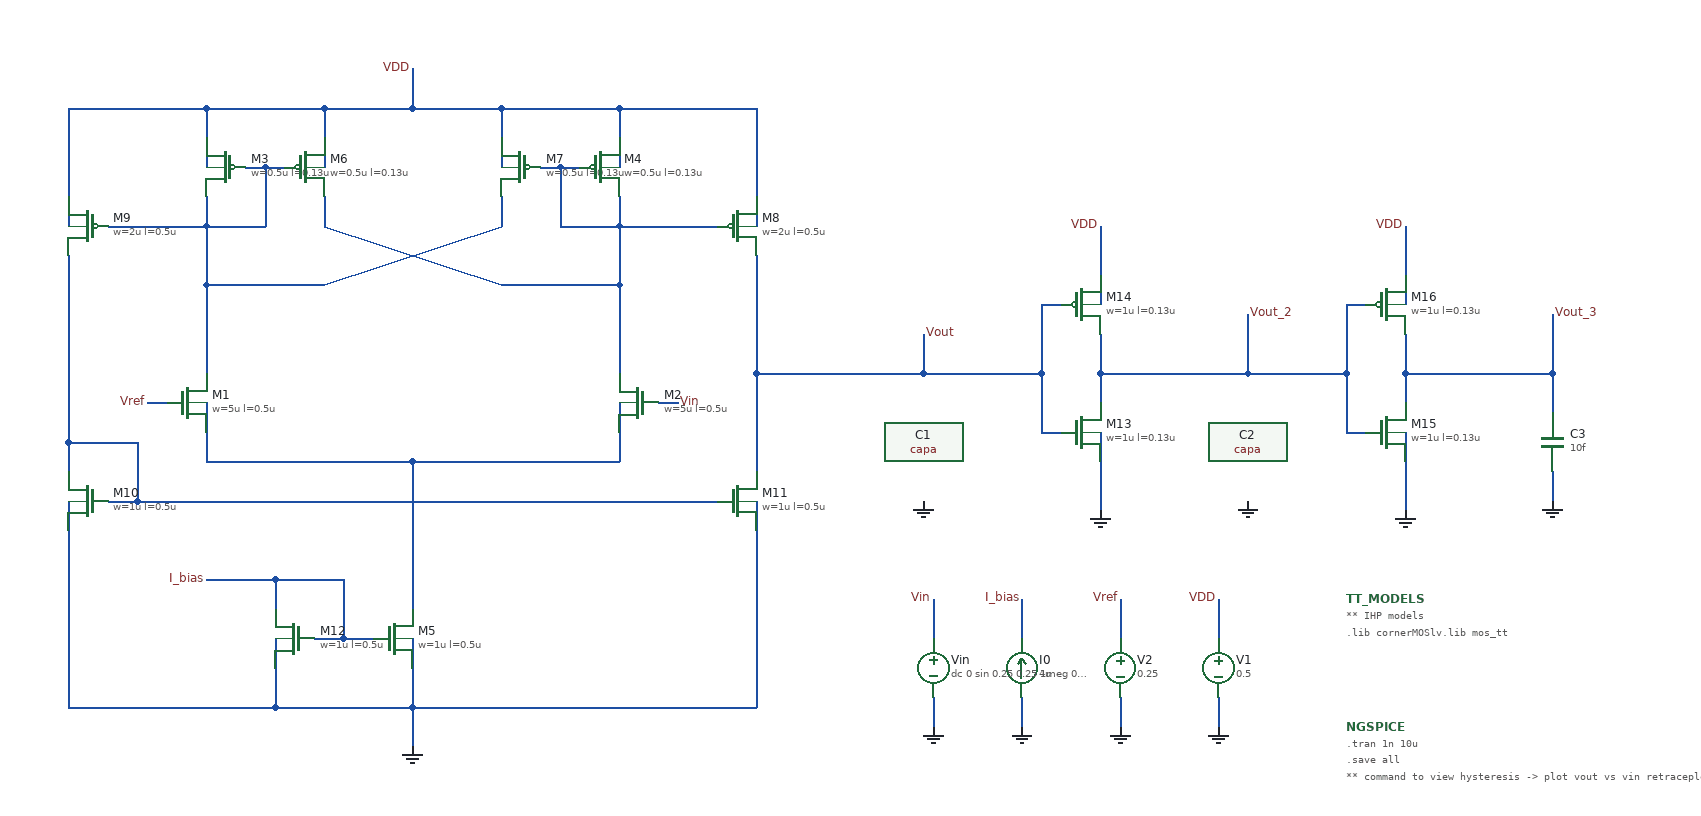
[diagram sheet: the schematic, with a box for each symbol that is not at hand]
v {xschem version=3.4.7 file_version=1.2}
G {}
K {}
V {}
S {}
E {}
P 4 1 1960 -820 {}
N 1310 -1370 1330 -1370 {lab=#net1}
N 1610 -1370 1630 -1370 {lab=#net2}
N 1370 -1250 1550 -1310 {lab=#net1}
N 1250 -1250 1370 -1250 {lab=#net1}
N 1370 -1310 1550 -1250 {lab=#net2}
N 1550 -1250 1670 -1250 {lab=#net2}
N 1250 -1250 1250 -1160 {lab=#net1}
N 1250 -1310 1250 -1250 {lab=#net1}
N 1370 -1340 1370 -1310 {lab=#net2}
N 1550 -1340 1550 -1310 {lab=#net1}
N 1670 -1250 1670 -1160 {lab=#net2}
N 1670 -1310 1670 -1250 {lab=#net2}
N 1310 -1370 1310 -1310 {lab=#net1}
N 1290 -1370 1310 -1370 {lab=#net1}
N 1250 -1310 1310 -1310 {lab=#net1}
N 1250 -1340 1250 -1310 {lab=#net1}
N 1610 -1370 1610 -1310 {lab=#net2}
N 1590 -1370 1610 -1370 {lab=#net2}
N 1610 -1310 1670 -1310 {lab=#net2}
N 1670 -1340 1670 -1310 {lab=#net2}
N 1250 -1430 1250 -1370 {lab=VDD}
N 1550 -1430 1670 -1430 {lab=VDD}
N 1670 -1430 1670 -1370 {lab=VDD}
N 1550 -1430 1550 -1370 {lab=VDD}
N 1460 -1430 1550 -1430 {lab=VDD}
N 1370 -1430 1370 -1370 {lab=VDD}
N 1250 -1430 1370 -1430 {lab=VDD}
N 1670 -1130 1670 -1070 {lab=#net3}
N 1250 -1130 1250 -1070 {lab=#net3}
N 1150 -1310 1250 -1310 {lab=#net1}
N 1110 -1430 1110 -1310 {lab=VDD}
N 1110 -1430 1250 -1430 {lab=VDD}
N 1810 -1430 1810 -1310 {lab=VDD}
N 1670 -1430 1810 -1430 {lab=VDD}
N 1810 -1160 1810 -1060 {lab=Vout}
N 1180 -1030 1770 -1030 {lab=#net4}
N 1110 -1090 1110 -1060 {lab=#net4}
N 1180 -1090 1180 -1030 {lab=#net4}
N 1150 -1030 1180 -1030 {lab=#net4}
N 1110 -1090 1180 -1090 {lab=#net4}
N 1110 -1280 1110 -1090 {lab=#net4}
N 1670 -1310 1770 -1310 {lab=#net2}
N 1460 -1070 1670 -1070 {lab=#net3}
N 1390 -890 1420 -890 {lab=I_bias}
N 1390 -950 1390 -890 {lab=I_bias}
N 1360 -890 1390 -890 {lab=I_bias}
N 1320 -950 1390 -950 {lab=I_bias}
N 1320 -950 1320 -920 {lab=I_bias}
N 1460 -1070 1460 -920 {lab=#net3}
N 1250 -1070 1460 -1070 {lab=#net3}
N 1460 -820 1810 -820 {lab=GND}
N 1110 -1030 1110 -820 {lab=GND}
N 1810 -1030 1810 -820 {lab=GND}
N 1320 -820 1460 -820 {lab=GND}
N 1250 -950 1320 -950 {lab=I_bias}
N 1710 -1130 1730 -1130 {lab=Vin}
N 1190 -1130 1210 -1130 {lab=Vref}
N 1460 -820 1460 -780 {lab=GND}
N 1460 -1470 1460 -1430 {lab=VDD}
N 1370 -1430 1460 -1430 {lab=VDD}
N 1810 -1160 1980 -1160 {lab=Vout}
N 1810 -1280 1810 -1160 {lab=Vout}
N 2180 -830 2180 -800 {lab=GND}
N 2080 -830 2080 -800 {lab=GND}
N 1990 -830 1990 -800 {lab=GND}
N 2180 -930 2180 -890 {lab=Vref}
N 2080 -930 2080 -890 {lab=I_bias}
N 1990 -930 1990 -890 {lab=Vin}
N 2280 -830 2280 -800 {lab=GND}
N 2280 -930 2280 -890 {lab=VDD}
N 1110 -820 1320 -820 {lab=GND}
N 1460 -890 1460 -820 {lab=GND}
N 1320 -890 1320 -820 {lab=GND}
N 2160 -1160 2160 -1130 {lab=Vout_2}
N 2100 -1100 2120 -1100 {lab=Vout}
N 2100 -1160 2100 -1100 {lab=Vout}
N 2100 -1230 2120 -1230 {lab=Vout}
N 1980 -1160 2100 -1160 {lab=Vout}
N 2100 -1230 2100 -1160 {lab=Vout}
N 2160 -1310 2160 -1230 {lab=VDD}
N 2160 -1100 2160 -1020 {lab=GND}
N 2160 -1160 2310 -1160 {lab=Vout_2}
N 2160 -1200 2160 -1160 {lab=Vout_2}
N 2470 -1160 2470 -1130 {lab=Vout_3}
N 2410 -1100 2430 -1100 {lab=Vout_2}
N 2410 -1230 2430 -1230 {lab=Vout_2}
N 2410 -1160 2410 -1100 {lab=Vout_2}
N 2470 -1310 2470 -1230 {lab=VDD}
N 2470 -1100 2470 -1020 {lab=GND}
N 2470 -1160 2620 -1160 {lab=Vout_3}
N 2470 -1200 2470 -1160 {lab=Vout_3}
N 2620 -1160 2620 -1120 {lab=Vout_3}
N 2620 -1060 2620 -1030 {lab=GND}
N 2310 -1160 2410 -1160 {lab=Vout_2}
N 2410 -1230 2410 -1160 {lab=Vout_2}
N 2310 -1220 2310 -1160 {lab=Vout_2}
N 1980 -1200 1980 -1160 {lab=Vout}
N 2620 -1220 2620 -1160 {lab=Vout_3}
C {sg13g2_pr/sg13_lv_pmos.sym} 1270 -1370 0 1 {name=M3
l=0.13u
w=0.5u
ng=1
m=1
model=sg13_lv_pmos
spiceprefix=X
}
C {sg13g2_pr/sg13_lv_pmos.sym} 1350 -1370 0 0 {name=M6
l=0.13u
w=0.5u
ng=1
m=1
model=sg13_lv_pmos
spiceprefix=X
}
C {sg13g2_pr/sg13_lv_pmos.sym} 1570 -1370 0 1 {name=M7
l=0.13u
w=0.5u
ng=1
m=1
model=sg13_lv_pmos
spiceprefix=X
}
C {sg13g2_pr/sg13_lv_pmos.sym} 1650 -1370 0 0 {name=M4
l=0.13u
w=0.5u
ng=1
m=1
model=sg13_lv_pmos
spiceprefix=X
}
C {sg13g2_pr/sg13_lv_nmos.sym} 1230 -1130 0 0 {name=M1
l=0.5u
w=5u
ng=1
m=1
model=sg13_lv_nmos
spiceprefix=X
}
C {sg13g2_pr/sg13_lv_nmos.sym} 1690 -1130 0 1 {name=M2
l=0.5u
w=5u
ng=1
m=1
model=sg13_lv_nmos
spiceprefix=X
}
C {sg13g2_pr/sg13_lv_nmos.sym} 1440 -890 0 0 {name=M5
l=0.5u
w=1u
ng=1
m=1
model=sg13_lv_nmos
spiceprefix=X
}
C {sg13g2_pr/sg13_lv_pmos.sym} 1130 -1310 0 1 {name=M9
l=0.5u
w=2u
ng=1
m=1
model=sg13_lv_pmos
spiceprefix=X}
C {sg13g2_pr/sg13_lv_pmos.sym} 1790 -1310 0 0 {name=M8
l=0.5u
w=2u
ng=1
m=1
model=sg13_lv_pmos
spiceprefix=X
}
C {sg13g2_pr/sg13_lv_nmos.sym} 1790 -1030 0 0 {name=M11
l=0.5u
w=1u
ng=1
m=1
model=sg13_lv_nmos
spiceprefix=X
}
C {sg13g2_pr/sg13_lv_nmos.sym} 1130 -1030 0 1 {name=M10
l=0.5u
w=1u
ng=1
m=1
model=sg13_lv_nmos
spiceprefix=X
}
C {sg13g2_pr/sg13_lv_nmos.sym} 1340 -890 0 1 {name=M12
l=0.5u
w=1u
ng=1
m=1
model=sg13_lv_nmos
spiceprefix=X
}
C {lab_pin.sym} 1190 -1130 0 0 {name=p2 sig_type=std_logic lab=Vref}
C {lab_pin.sym} 1730 -1130 0 1 {name=p3 sig_type=std_logic lab=Vin}
C {capa.sym} 1980 -1090 0 0 {name=C1
m=1
value=10f
footprint=1206
device="ceramic capacitor"}
C {gnd.sym} 1980 -1030 0 0 {name=l1 lab=GND}
C {gnd.sym} 1460 -780 0 0 {name=l2 lab=GND}
C {lab_pin.sym} 1460 -1470 0 0 {name=p4 sig_type=std_logic lab=VDD}
C {lab_pin.sym} 1250 -950 0 0 {name=p1 sig_type=std_logic lab=I_bias}
C {vsource.sym} 2180 -860 0 0 {name=V2 value=0.25 savecurrent=false}
C {gnd.sym} 2180 -800 0 0 {name=l4 lab=GND}
C {isource.sym} 2080 -860 2 1 {name=I0 value=4u}
C {vsource.sym} 1990 -860 0 1 {name=Vin value="dc 0 sin 0.25 0.25 1meg 0 0 270" savecurrent=false}
C {gnd.sym} 1990 -800 0 0 {name=l6 lab=GND}
C {lab_pin.sym} 2180 -930 0 0 {name=p5 sig_type=std_logic lab=Vref}
C {lab_pin.sym} 2080 -930 0 0 {name=p7 sig_type=std_logic lab=I_bias}
C {lab_pin.sym} 1990 -930 0 0 {name=p8 sig_type=std_logic lab=Vin}
C {vsource.sym} 2280 -860 0 0 {name=V1 value=0.5 savecurrent=false}
C {gnd.sym} 2280 -800 0 0 {name=l3 lab=GND}
C {lab_pin.sym} 2280 -930 0 0 {name=p9 sig_type=std_logic lab=VDD}
C {code_shown.sym} 2410 -930 0 0 {
name=TT_MODELS
only_toplevel=true
value="
** IHP models
.lib cornerMOSlv.lib mos_tt
"
spice_ignore=false
      }
C {code_shown.sym} 2410 -800 0 0 {name=NGSPICE only_toplevel=false
value="
.tran 1n 10u
.save all
** command to view hysteresis -> plot vout vs vin retraceplot
"}
C {sg13g2_pr/sg13_lv_nmos.sym} 2140 -1100 0 0 {name=M13
l=0.13u
w=1u
ng=1
m=1
model=sg13_lv_nmos
spiceprefix=X
}
C {sg13g2_pr/sg13_lv_pmos.sym} 2140 -1230 0 0 {name=M14
l=0.13u
w=1u
ng=1
m=2
model=sg13_lv_pmos
spiceprefix=X
}
C {gnd.sym} 2160 -1020 0 0 {name=l5 lab=GND}
C {lab_pin.sym} 2160 -1310 0 0 {name=p11 sig_type=std_logic lab=VDD}
C {capa.sym} 2310 -1090 0 0 {name=C2
m=1
value=10f
footprint=1206
device="ceramic capacitor"}
C {gnd.sym} 2310 -1030 0 0 {name=l7 lab=GND}
C {lab_pin.sym} 1980 -1200 0 1 {name=p12 sig_type=std_logic lab=Vout}
C {sg13g2_pr/sg13_lv_nmos.sym} 2450 -1100 0 0 {name=M15
l=0.13u
w=1u
ng=1
m=10
model=sg13_lv_nmos
spiceprefix=X
}
C {sg13g2_pr/sg13_lv_pmos.sym} 2450 -1230 0 0 {name=M16
l=0.13u
w=1u
ng=1
m=20
model=sg13_lv_pmos
spiceprefix=X
}
C {gnd.sym} 2470 -1020 0 0 {name=l8 lab=GND}
C {lab_pin.sym} 2470 -1310 0 0 {name=p13 sig_type=std_logic lab=VDD}
C {capa.sym} 2620 -1090 0 0 {name=C3
m=1
value=10f
footprint=1206
device="ceramic capacitor"}
C {gnd.sym} 2620 -1030 0 0 {name=l9 lab=GND}
C {lab_pin.sym} 2310 -1220 0 1 {name=p6 sig_type=std_logic lab=Vout_2}
C {lab_pin.sym} 2620 -1220 0 1 {name=p14 sig_type=std_logic lab=Vout_3
}
C {gnd.sym} 2080 -800 0 0 {name=l10 lab=GND}
